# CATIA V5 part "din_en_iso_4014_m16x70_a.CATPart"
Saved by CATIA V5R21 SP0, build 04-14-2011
Part number: din_en_iso_4014_m16x70_a
Definition: Sechskantschrauben mit Schaft, Produktklassen A und B, DIN EN ISO 4014 - M16 x 70
Description: Sechskantschrauben mit Schaft, Produktklassen A und B, DIN EN ISO 4014 - M16 x 70
Property "REFERENCE": "DIN EN ISO 4014 - d M16 x l 70 - A"
Property "REFERENCE": "DIN EN ISO 4014 - d M16 x l 70 - A"
Property "STANDARD": "DIN EN ISO 4014"
Property "STANDARD": "DIN EN ISO 4014"
Property "DESIGN": "Sechskantschrauben mit Schaft, Produktklassen A und B, DIN EN ISO 4014 - M16 x 70"
Property "DESIGN": "Sechskantschrauben mit Schaft, Produktklassen A und B, DIN EN ISO 4014 - M16 x 70"
Property "OMNICLASS23": "23.13.23.11.13.19"
Property "OMNICLASS23": "23.13.23.11.13.19"
Property "TraceParts.PartStandardAcronym": "DIN"
Property "TraceParts.PartStatus": "Published"
Property "TraceParts.PartNumber": "32-19062013-068229"
Property "TraceParts.InstanceId": "32-19062013-068229QCKPDNEC0UNVGFOW9NMW0LKH"
Property "TraceParts.PartLanguage": "de"
Property "TraceParts.PartTitle": "Sechskantschrauben mit Schaft, Produktklassen A und B"
Property "TraceParts.PartVersion": "1.1.9"
Property "TRACEPARTS": "TRACEPARTS"
Property "TraceParts.ClassPath": "DIN:32-19062013-068229"
Bounding box of the stored display mesh (mm): x -12 to 12, y -13.856 to 13.856, z -10 to 70
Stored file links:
  C:\TPO v2\SharedFS\Outgoing\din_en_iso_4014_m16x70_a.CATPart

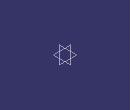
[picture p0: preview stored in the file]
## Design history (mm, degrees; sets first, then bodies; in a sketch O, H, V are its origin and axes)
AxisSystem1: origin (0, 0, 0), X (1, 0, 0), Y (0, 1, 0), Z (0, 0, 1)
Body1 "din_en_iso_4014_m16x70_a" (main body)
  Solid1: solid without history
